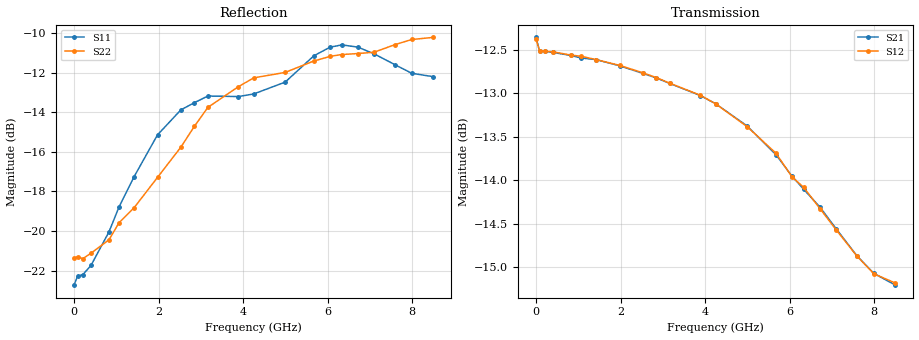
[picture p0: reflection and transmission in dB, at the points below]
! device id: pe43620
! dir: c:\dsa\pe43620\data\pe43620\-40c\3p300v\12p00db
! Serial: 1001
! Insertion: A
! Temp: -40C
! VDD: 3.300V
! Attenuation Step: 12.00dB
! IDD: 8.564525e-03mA
! FILE NAME
! DATE 10-22-2008 14:40:18
! CORRECTED  DATA
#  Hz  S  RI  R  50.00
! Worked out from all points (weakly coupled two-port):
!   401 points, 300 kHz to 8.5 GHz, reference 50 ohm
!   highest |S21| = -12.36 dB at 300 kHz (marker M1); lowest = -15.2 dB at 8.5 GHz (marker M2)
!   lowest |S11| = -22.7 dB at 300 kHz (marker M3), VSWR 1.16, Z = 43.2 + j0.0298 ohm
!   |S11| at or under -10 dB: start of sweep to end of sweep
!   |S22| runs from -21.4 to -10.2 dB; largest |S21 - S12| = 0.0009
!   S11 on the Smith chart (normalised r, x): 300 kHz: 0.86, +0.00; 3.889 GHz: 0.66, -0.12; 8.5 GHz: 0.65, +0.22
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300000  -0.073 0.000343  0.2411 3.48e-05  0.2407 0.000447  -0.0856 0.000159
8.5297e7  -0.0768 -0.00159  0.2368 -0.00385  0.2369 -0.00383  -0.0861 -0.00248
2.127925e8  -0.0776 -0.00215  0.2366 -0.00854  0.2366 -0.00846  -0.085 -0.00554
4.040358e8  -0.0818 -0.00399  0.2358 -0.0159  0.236 -0.0159  -0.0873 -0.0104
8.290208e8  -0.0984 -0.0151  0.2332 -0.0321  0.2333 -0.0321  -0.0923 -0.0227
1.062763e9  -0.1124 -0.0237  0.231 -0.0411  0.2315 -0.0414  -0.1003 -0.0305
1.424e9  -0.1313 -0.0402  0.2275 -0.0552  0.2275 -0.0552  -0.1087 -0.0363
1.97648e9  -0.1587 -0.0739  0.2195 -0.0758  0.2197 -0.0756  -0.1277 -0.0487
2.528961e9  -0.176 -0.1  0.209 -0.0957  0.2092 -0.0957  -0.1544 -0.0522
2.8477e9  -0.181 -0.1086  0.2023 -0.1062  0.2025 -0.1061  -0.1753 -0.0556
3.166438e9  -0.1885 -0.1123  0.1951 -0.1157  0.1949 -0.1162  -0.1937 -0.0682
3.888913e9  -0.1992 -0.0904  0.1771 -0.1359  0.1772 -0.1359  -0.2199 -0.073
4.25015e9  -0.2108 -0.0698  0.1674 -0.144  0.1673 -0.1441  -0.2328 -0.0726
4.993874e9  -0.2369 -0.0215  0.1468 -0.1563  0.1461 -0.1567  -0.2476 -0.0455
5.67385e9  -0.2773 0.00282  0.1246 -0.1646  0.1246 -0.1651  -0.2688 -0.0113
6.056336e9  -0.2912 0.0147  0.1115 -0.1668  0.1116 -0.1665  -0.2762 0.00963
6.332577e9  -0.2947 0.0215  0.1032 -0.168  0.1032 -0.1686  -0.2783 0.0245
6.715063e9  -0.2893 0.0371  0.0898 -0.1704  0.0901 -0.1698  -0.2768 0.0481
7.09755e9  -0.2747 0.0567  0.077 -0.1706  0.0766 -0.1705  -0.2723 0.0776
7.586282e9  -0.248 0.089  0.0624 -0.1695  0.0622 -0.1695  -0.2725 0.1151
7.990018e9  -0.2211 0.1176  0.0538 -0.168  0.0535 -0.168  -0.2737 0.1344
8.5e9  -0.1878 0.1582  0.0452 -0.1677  0.0452 -0.1682  -0.261 0.1648
